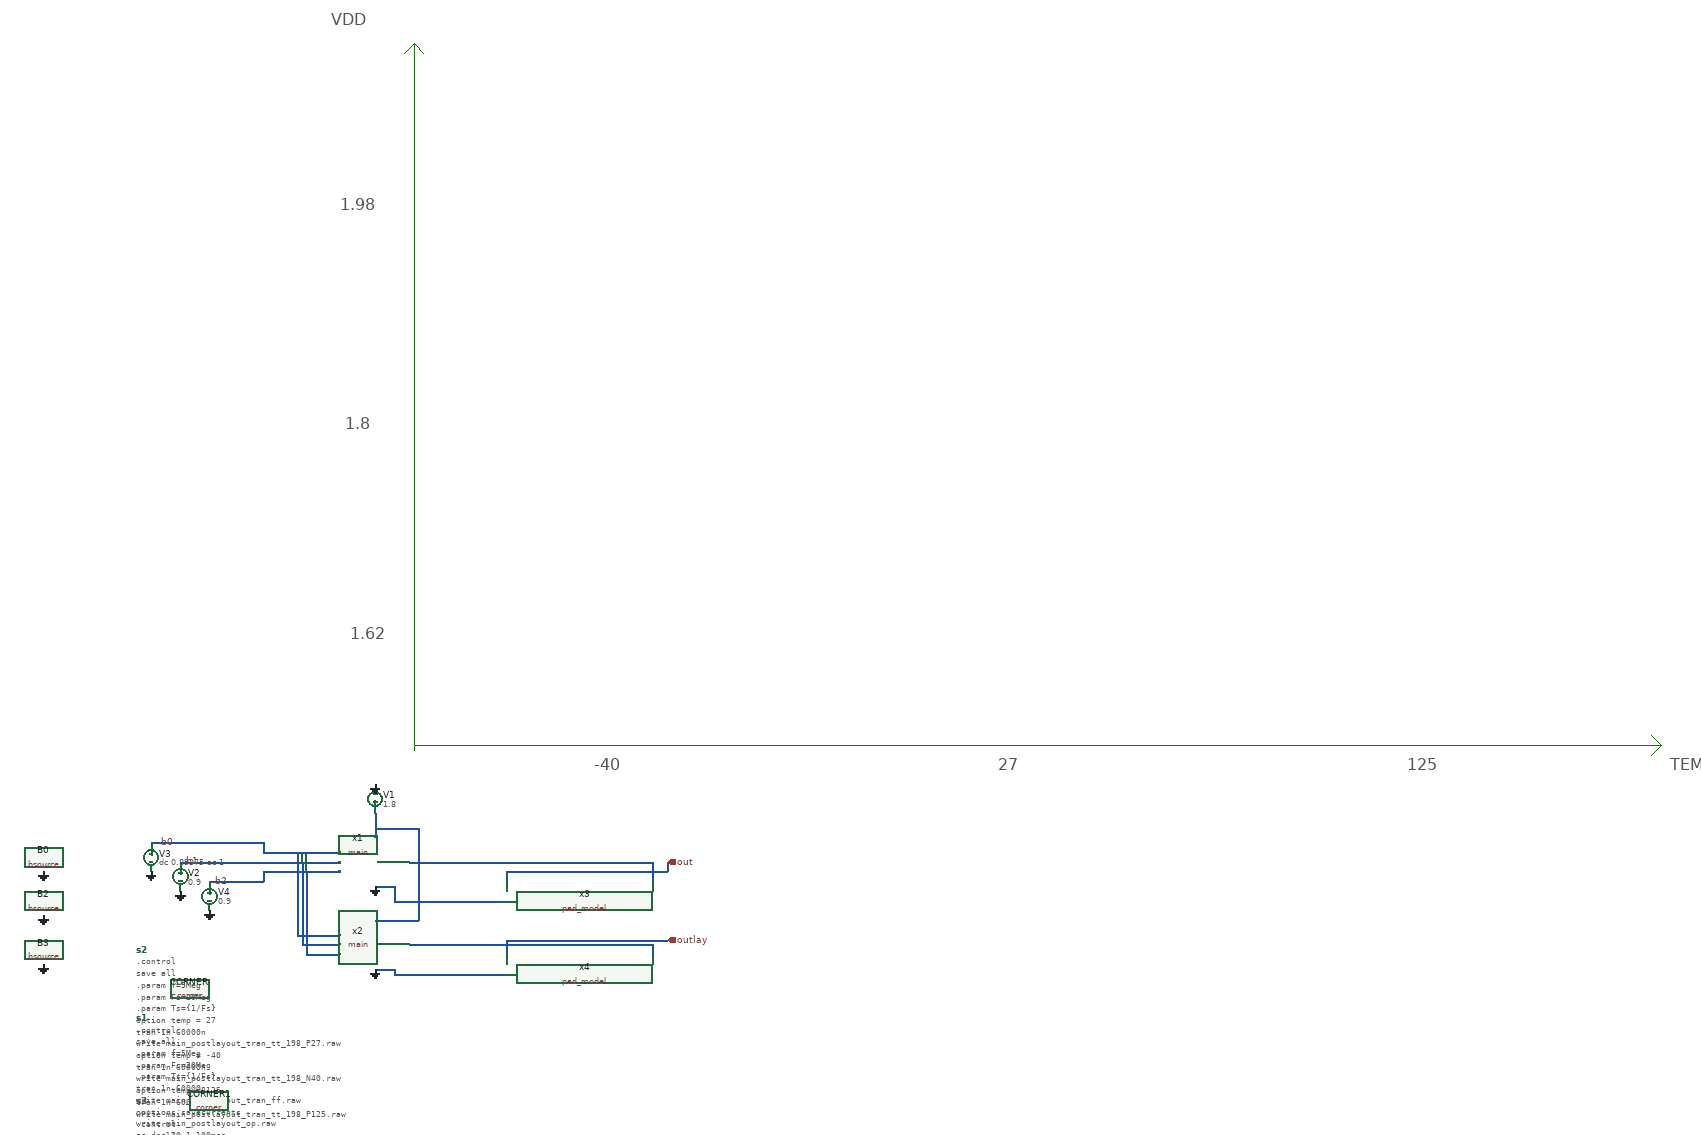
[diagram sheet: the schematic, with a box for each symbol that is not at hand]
v {xschem version=3.4.8RC file_version=1.3}
G {}
K {}
V {}
S {}
F {}
E {}
L 4 -420 -140 2140 -140 {}
L 4 2120 -160 2140 -140 {}
L 4 2120 -120 2140 -140 {}
L 4 -420 -1580 -420 -130 {}
L 4 -440 -1560 -420 -1580 {}
L 4 -420 -1580 -400 -1560 {}
B 2 420 -990 1220 -590 {flags=graph
y1=0.7
y2=1.1
ypos1=0
ypos2=2
divy=5
subdivy=1
unity=1
x1=2901290.8
x2=3921321.9
divx=5
subdivx=1
xlabmag=1.0
ylabmag=1.0
node="out
outlay
x1.v_dac"
color="4 7 6"
dataset=-1
unitx=1
logx=0
logy=0
rawfile=$netlist_dir/main_postlayout_tran_tt_18_P27.raw
hilight_wave=-1}
B 2 430 350 1230 750 {flags=graph
y1=1.5e-05
y2=0.33
ypos1=0
ypos2=2
divy=5
subdivy=4
unity=1
x1=2901290.8
x2=3921321.9
divx=5
subdivx=1
xlabmag=1.0
ylabmag=1.0
node="out
outlay"
color="7 18"
dataset=-1
unitx=1
logx=0
logy=0
rawfile=$netlist_dir/main_postlayout_tb_mc.raw}
B 2 430 770 1230 1170 {flags=graph
y1=-7.8
y2=180
ypos1=0
ypos2=2
divy=5
subdivy=1
unity=1
x1=2901290.8
x2=3921321.9
divx=5
subdivx=1
xlabmag=1.0
ylabmag=1.0
node="ph(out)
ph(outlay)"
color="12 13"
dataset=-1
unitx=1
logx=0
logy=0
}
B 2 -400 -990 400 -590 {flags=graph
y1=0.37
y2=1.2
ypos1=0
ypos2=2
divy=5
subdivy=1
unity=1
x1=2901290.8
x2=3921321.9
divx=5
subdivx=1
xlabmag=1.0
ylabmag=1.0
node="out
outlay
x1.v_dac"
color="4 7 6"
dataset=-1
unitx=1
logx=0
logy=0
rawfile=$netlist_dir/main_postlayout_tran_tt_18_N40.raw
hilight_wave=-1}
B 2 1240 -990 2040 -590 {flags=graph
y1=0.79
y2=1
ypos1=0
ypos2=2
divy=5
subdivy=1
unity=1
x1=2901290.8
x2=3921321.9
divx=5
subdivx=1
xlabmag=1.0
ylabmag=1.0
node="out
outlay
x1.v_dac"
color="4 7 6"
dataset=-1
unitx=1
logx=0
logy=0
rawfile=$netlist_dir/main_postlayout_tran_tt_18_P125.raw
hilight_wave=-1}
B 2 420 -1410 1220 -1010 {flags=graph
y1=0.82
y2=1.2
ypos1=0
ypos2=2
divy=5
subdivy=1
unity=1
x1=2901290.8
x2=3921321.9
divx=5
subdivx=1
xlabmag=1.0
ylabmag=1.0
node="out
outlay
x1.v_dac"
color="4 7 6"
dataset=-1
unitx=1
logx=0
logy=0
rawfile=$netlist_dir/main_postlayout_tran_tt_198_P27.raw
hilight_wave=-1}
B 2 -400 -1410 400 -1010 {flags=graph
y1=0.73
y2=1.2
ypos1=0
ypos2=2
divy=5
subdivy=1
unity=1
x1=2901290.8
x2=3921321.9
divx=5
subdivx=1
xlabmag=1.0
ylabmag=1.0
node="out
outlay
x1.v_dac"
color="4 7 6"
dataset=-1
unitx=1
logx=0
logy=0
rawfile=$netlist_dir/main_postlayout_tran_tt_198_N40.raw
hilight_wave=-1}
B 2 1240 -1410 2040 -1010 {flags=graph
y1=0.87
y2=1.1
ypos1=0
ypos2=2
divy=5
subdivy=1
unity=1
x1=2901290.8
x2=3921321.9
divx=5
subdivx=1
xlabmag=1.0
ylabmag=1.0
node="out
outlay
x1.v_dac"
color="4 7 6"
dataset=-1
unitx=1
logx=0
logy=0
rawfile=$netlist_dir/main_postlayout_tran_tt_198_P125.raw
hilight_wave=-1}
B 2 420 -570 1220 -170 {flags=graph
y1=0.53282065
y2=0.92680465
ypos1=0
ypos2=2
divy=5
subdivy=1
unity=1
x1=2901290.8
x2=3921321.9
divx=5
subdivx=1
xlabmag=1.0
ylabmag=1.0
node="out
outlay
x1.v_dac"
color="4 7 6"
dataset=-1
unitx=1
logx=0
logy=0
rawfile=$netlist_dir/main_postlayout_tran_tt_162_P27.raw
hilight_wave=-1}
B 2 -400 -570 400 -170 {flags=graph
y1=0.71
y2=0.9
ypos1=0
ypos2=2
divy=5
subdivy=1
unity=1
x1=2901290.8
x2=3921321.9
divx=5
subdivx=1
xlabmag=1.0
ylabmag=1.0
node="out
outlay
x1.v_dac"
color="4 7 6"
dataset=-1
unitx=1
logx=0
logy=0
rawfile=$netlist_dir/main_postlayout_tran_tt_162_N40.raw
hilight_wave=-1}
B 2 1240 -570 2040 -170 {flags=graph
y1=0.71
y2=0.9
ypos1=0
ypos2=2
divy=5
subdivy=1
unity=1
x1=2901290.8
x2=3921321.9
divx=5
subdivx=1
xlabmag=1.0
ylabmag=1.0
node="out
outlay
x1.v_dac"
color="4 7 6"
dataset=-1
unitx=1
logx=0
logy=0
rawfile=$netlist_dir/main_postlayout_tran_tt_162_P125.raw
hilight_wave=-1}
T {VDD} -590 -1640 0 0 1 1 {}
T {TEMPERATURE} 2160 -110 0 0 1 1 {}
T {1.98} -570 -1260 0 0 1 1 {}
T {1.8} -560 -810 0 0 1 1 {}
T {1.62} -550 -380 0 0 1 1 {}
T {-40} -50 -110 0 0 1 1 {}
T {27} 780 -110 0 0 1 1 {}
T {125} 1620 -110 0 0 1 1 {}
N -960 60 -740 60 {lab=b0}
N -900 100 -740 100 {lab=b1}
N -840 140 -740 140 {lab=b2}
N -740 100 -730 100 {lab=b1}
N -730 60 -730 80 {lab=b0}
N -740 60 -730 60 {lab=b0}
N -740 140 -730 140 {lab=b2}
N -730 120 -730 140 {lab=b2}
N -500 0 -500 50 {lab=#net1}
N -730 80 -570 80 {lab=b0}
N -730 100 -570 100 {lab=b1}
N -730 120 -570 120 {lab=b2}
N -660 80 -660 250 {lab=b0}
N -660 250 -570 250 {lab=b0}
N -650 100 -650 270 {lab=b1}
N -650 270 -570 270 {lab=b1}
N -640 120 -640 290 {lab=b2}
N -640 290 -570 290 {lab=b2}
N -500 30 -410 30 {lab=#net1}
N -410 30 -410 220 {lab=#net1}
N -500 220 -410 220 {lab=#net1}
N -500 150 -460 150 {lab=0}
N -460 150 -460 160 {lab=0}
N -500 320 -460 320 {lab=0}
N -460 320 -460 330 {lab=0}
N -460 180 -230 180 {lab=0}
N -460 160 -460 180 {lab=0}
N -430 100 70 100 {lab=#net2}
N 70 100 70 140 {lab=#net2}
N -230 120 -230 140 {lab=out}
N -230 120 100 120 {lab=out}
N 100 100 100 120 {lab=out}
N -460 330 -230 330 {lab=0}
N -430 270 70 270 {lab=#net3}
N 70 270 70 290 {lab=#net3}
N -230 260 -230 290 {lab=outlay}
N -230 260 100 260 {lab=outlay}
C {sky130_fd_pr/corner.sym} -880 360 0 0 {name=CORNER only_toplevel=true corner=tt
spice_ignore=true}
C {gnd.sym} -1180 210 0 0 {name=l11 lab=0}
C {gnd.sym} -1180 120 0 0 {name=l12 lab=0}
C {lab_wire.sym} -910 60 0 0 {name=p3 sig_type=std_logic lab=b0}
C {lab_wire.sym} -860 100 0 0 {name=p4 sig_type=std_logic lab=b1}
C {gnd.sym} -1180 310 0 0 {name=l13 lab=0}
C {lab_wire.sym} -800 140 0 0 {name=p5 sig_type=std_logic lab=b2}
C {bsource.sym} -1180 90 0 0 {name=B0 VAR=V FUNC="'(((time-floor(time/200n)*200n)>=50n && (time-floor(time/200n)*200n)<75n) || ((time-floor(time/200n)*200n)>=125n && (time-floor(time/200n)*200n)<150n) || ((time-floor(time/200n)*200n)>=175n && (time-floor(time/200n)*200n)<200n)) ? 1.8 : 0'" m=1}
C {bsource.sym} -1180 180 0 0 {name=B2 VAR=V FUNC="'((time-floor(time/200n)*200n)>=25n && (time-floor(time/200n)*200n)<100n) ? 1.8 : 0'" m=1}
C {bsource.sym} -1180 280 0 0 {name=B3 VAR=V FUNC="'(time-floor(time/200n)*200n)<125n ? 1.8 : 0'" m=1}
C {opin.sym} 100 100 0 0 {name=p1 lab=out}
C {vsource.sym} -500 -30 2 0 {name=V1 value=1.8 savecurrent=false}
C {gnd.sym} -500 -60 2 0 {name=l2 lab=0}
C {code.sym} -990 420 0 0 {name=s1 only_toplevel=false value="
.control
save all
.param f=5Meg
.param Fs=20Meg
.param Ts=\{1/Fs\}
tran 1n 60000n
write main_postlayout_tran_ff.raw
op
write main_postlayout_op.raw
ac dec 20 1 100meg
write main_postlayout_ac.raw
.endc"
spice_ignore=true}
C {main.sym} -500 100 0 0 {name=x1}
C {gnd.sym} -500 150 0 0 {name=l1 lab=0}
C {main.sym} -500 270 0 0 {name=x2
schematic=main_parax
spice_sym_def="tcleval(.include [file normalize ../mag/main.sim.spice])"}
C {gnd.sym} -500 320 0 0 {name=l3 lab=0}
C {opin.sym} 100 260 0 0 {name=p2 lab=outlay}
C {pad_model.sym} -80 160 0 0 {name=x3}
C {pad_model.sym} -80 310 0 0 {name=x4}
C {code.sym} -990 280 0 0 {name=s2 only_toplevel=false value="
.control
save all
.param f=5Meg
.param Fs=20Meg
.param Ts=\{1/Fs\}
option temp = 27
tran 1n 60000n
write main_postlayout_tran_tt_198_P27.raw
option temp = -40
tran 1n 60000n
write main_postlayout_tran_tt_198_N40.raw
option temp = 125
tran 1n 60000n
write main_postlayout_tran_tt_198_P125.raw
.endc"
spice_ignore=true}
C {sky130_fd_pr/corner.sym} -840 590 0 0 {name=CORNER1 only_toplevel=false corner=tt_mm}
C {code.sym} -990 590 0 0 {name=s3 only_toplevel=false value=".options savecurrents
.control
save all
.param f=5Meg
.param Fs=20Meg
.param Ts=\{1/Fs\}
let mc_runs = 100
let mc_runs_post = mc_runs
  let mc_run = 1
  let mc_run_post = 1
  let results_f0   = unitvec(mc_runs)
  let results_Q    = unitvec(mc_runs)
  let results_gain = unitvec(mc_runs)
  let results_gain_max_var = unitvec(mc_runs)
  let results_f0_post   = unitvec(mc_runs_post)
  let results_Q_post    = unitvec(mc_runs_post)
  let results_gain_post = unitvec(mc_runs_post)
  let results_gain_max_var_post = unitvec(mc_runs_post)

  dowhile mc_run <= mc_runs
    reset
    ac dec 200 1 10meg

    * Guadagno DC (al primo punto dello sweep, 1Hz)
    meas ac gain_dc  FIND vdb(out) AT=1
    meas ac gain_dc_post  FIND vdb(outlay) AT=1
    * Guadagno di picco (massimo su tutto lo sweep)
    let vout_db = vdb(out)
    let freqvec = frequency
    let n = length(vout_db)
    let imax = 0
    let vmax = vout_db[0]
    let i = 1
    dowhile i < n
      if vout_db[i] > vmax
        let vmax = vout_db[i]
        let imax = i
      end
      let i = i + 1
    end
    let f0_meas = freqvec[imax]
    let gain_max = vmax
    echo Gain = $&gain_max dB
    echo F0 = $&f0_meas Hz

    let vout_db_post = vdb(outlay)
    let freqvec_post = frequency
    let n = length(vout_db_post)
    let imax_post = 0
    let vmax_post = vout_db_post[0]
    let l = 1
    dowhile l < n
      if vout_db_post[l] > vmax_post
        let vmax_post = vout_db_post[l]
        let imax_post = l
      end
      let l = l + 1
    end
    let f0_meas_post = freqvec_post[imax_post]
    let gain_max_post = vmax_post
    echo GainPost = $&gain_max_post dB
    echo F0Post = $&f0_meas_post Hz

    let gain_dc_run  = gain_dc
    let gain_dc_run_post  = gain_dc_post
    let gain_max_run = gain_max
    let gain_max_run_post = gain_max_post
    let f0_run       = f0_meas
    let f0_run_post  = f0_meas_post
    let GG = (gain_max_run-gain_dc_run)/20
    let GG_post = (gain_max_run_post-gain_dc_run_post)/20
    let Q_run        = 10^(GG)
    let Q_run_post   = 10^(GG_post)

    set gain_save = $&gain_dc_run
    set gain_max_save = $&gain_max_run
    set f0_save   = $&f0_run
    set q_save    = $&Q_run
    set run_save  = $&mc_run
    set gain_save_post = $&gain_dc_run_post
    set gain_max_save_post = $&gain_max_run_post
    set f0_save_post  = $&f0_run_post
    set q_save_post   = $&Q_run_post
    set run_save_post  = $&mc_run_post

    echo Run $&mc_run: f0=$&f0_run Hz  Q=$&Q_run  gainDC=$&gain_dc_run dB  gainMAX=$&gain_max_run dB
    echo Run $&mc_run_post: f0_post=$&f0_run_post Hz  Q_post=$&Q_run_post  gainDC_post=$&gain_dc_run_post dB gainMAXpost=$&gain_max_run_post dB

    let f0_run   = $f0_save
    let Q_run    = $q_save
    let gain_run = $gain_save
    let gain_max_var = $gain_max_save
    let mc_run   = $run_save
    let f0_run_post   = $f0_save_post
    let Q_run_post    = $q_save_post
    let gain_run_post = $gain_save_post
    let gain_max_var_post = $gain_max_save_post
    let mc_run_post   = $run_save_post

    let results_f0[mc_run - 1]   = f0_run
    let results_Q[mc_run - 1]    = Q_run
    let results_gain[mc_run - 1] = gain_run
    let results_gain_max_var[mc_run - 1] = gain_max_var
    let results_f0_post[mc_run_post - 1]   = f0_run_post
    let results_Q_post[mc_run_post - 1]    = Q_run_post
    let results_gain_post[mc_run_post - 1] = gain_run_post
    let results_gain_max_var_post[mc_run_post - 1] = gain_max_var_post

    remzerovec
    write main_postlayout_tb_mc.raw
    set appendwrite
    let mc_run = mc_run + 1
    let mc_run_post = mc_run_post + 1
  end

  * Statistiche finali per ciascun parametro
  let mean_f0 = mean(results_f0)
  let sigma_f0 = sqrt((mean(results_f0*results_f0) - mean_f0*mean_f0) * mc_runs / (mc_runs - 1))
  let mean_f0_post = mean(results_f0_post)
  let sigma_f0_post = sqrt((mean(results_f0_post*results_f0_post) - mean_f0_post*mean_f0_post) * mc_runs / (mc_runs - 1))

  let mean_Q = mean(results_Q)
  let sigma_Q = sqrt((mean(results_Q*results_Q) - mean_Q*mean_Q) * mc_runs / (mc_runs - 1))
  let mean_Q_post = mean(results_Q_post)
  let sigma_Q_post = sqrt((mean(results_Q_post*results_Q_post) - mean_Q_post*mean_Q_post) * mc_runs / (mc_runs - 1))

  let mean_gain = mean(results_gain)
  let sigma_gain = sqrt((mean(results_gain*results_gain) - mean_gain*mean_gain) * mc_runs / (mc_runs - 1))
  let mean_gain_post = mean(results_gain_post)
  let sigma_gain_post = sqrt((mean(results_gain_post*results_gain_post) - mean_gain_post*mean_gain_post) * mc_runs / (mc_runs - 1))
  
  let mean_gain_max = mean(results_gain_max_var)
  let sigma_gain_max = sqrt((mean(results_gain_max_var*results_gain_max_var) - mean_gain_max*mean_gain_max) * mc_runs / (mc_runs - 1))
  let mean_gain_max_post = mean(results_gain_max_var_post)
  let sigma_gain_max_post = sqrt((mean(results_gain_max_var_post*results_gain_max_var_post) - mean_gain_max_post*mean_gain_max_post) * mc_runs_post / (mc_runs_post - 1))

  echo ======================================
  echo Monte Carlo completato ($&mc_runs run)
  echo f0:   media=$&mean_f0 Hz   sigma=$&sigma_f0 Hz
  echo Q:    media=$&mean_Q       sigma=$&sigma_Q
  echo GainDC: media=$&mean_gain dB sigma=$&sigma_gain dB
  echo GainMax: media=$&mean_gain_max dB sigma=$&sigma_gain_max dB
  echo f0_post:   media=$&mean_f0_post Hz   sigma=$&sigma_f0_post Hz
  echo Q_post:    media=$&mean_Q_post       sigma=$&sigma_Q_post
  echo GainDC_post: media=$&mean_gain_post dB sigma=$&sigma_gain_post dB
  echo GainMax_post: media=$&mean_gain_max_post dB sigma=$&sigma_gain_max_post dB
  echo ======================================

  print results_f0 > tb_mc_f0.txt
  print results_Q > tb_mc_Q.txt
  print results_gain > tb_mc_gain.txt
  print results_f0_post > tb_mc_f0_post.txt
  print results_Q_post > tb_mc_Q_post.txt
  print results_gain_post > tb_mc_gain_post.txt
.endc"}
C {vsource.sym} -960 90 0 0 {name=V3 value="dc 0.89375 ac 1" savecurrent=false}
C {gnd.sym} -960 120 0 0 {name=l10 lab=0}
C {vsource.sym} -900 130 0 0 {name=V2 value=0.9 savecurrent=false}
C {gnd.sym} -900 160 0 0 {name=l4 lab=0
value=0.9}
C {vsource.sym} -840 170 0 0 {name=V4 value=0.9 savecurrent=false}
C {gnd.sym} -840 200 0 0 {name=l5 lab=0
value=0.9}
